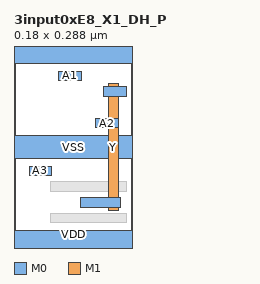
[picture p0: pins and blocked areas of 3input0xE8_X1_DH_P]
MACRO 3input0xE8_X1_DH_P
  CLASS CORE ;
  ORIGIN 0 0 ;
  FOREIGN 3input0xE8_X1_DH_P 0 0 ;
  SIZE 0.1800 BY 0.2880 ;
  SYMMETRY X Y ;
  SITE coresite ;
  PIN A1
    DIRECTION INPUT ;
    USE SIGNAL ;
    PORT
      LAYER M0 ;
        RECT 0.0680 0.2450 0.1020 0.2590 ;
    END
  END A1
  PIN A2
    DIRECTION INPUT ;
    USE SIGNAL ;
    PORT
      LAYER M0 ;
        RECT 0.1230 0.1730 0.1580 0.1870 ;
    END
  END A2
  PIN A3
    DIRECTION INPUT ;
    USE SIGNAL ;
    PORT
      LAYER M0 ;
        RECT 0.0230 0.1010 0.0570 0.1150 ;
    END
  END A3
  PIN Y
    DIRECTION OUTPUT ;
    USE SIGNAL ;
    PORT
      LAYER M1 ;
        RECT 0.1430 0.0480 0.1580 0.2400 ;
      LAYER M0 ;
        RECT 0.1010 0.0530 0.1620 0.0670 ;
        RECT 0.1350 0.2210 0.1700 0.2350 ;
    END
  END Y
  PIN VDD
    DIRECTION INOUT ;
    USE POWER ;
    SHAPE ABUTMENT ;
    PORT
      LAYER M0 ;
        RECT 0.0000 -0.0180 0.1800 0.0180 ;
        RECT 0.0000 0.2700 0.1800 0.3060 ;
    END
  END VDD
  PIN VSS
    DIRECTION INOUT ;
    USE GROUND ;
    SHAPE ABUTMENT ;
    PORT
      LAYER M0 ;
        RECT 0.0000 0.1260 0.1800 0.1620 ;
    END
  END VSS
  OBS
    LAYER V0 ;
      RECT 0.1430 0.0530 0.1570 0.0670 ;
      RECT 0.1430 0.2210 0.1570 0.2350 ;
    LAYER M0 ;
      RECT 0.0560 0.0290 0.1700 0.0430 ;
      RECT 0.0560 0.0770 0.1700 0.0910 ;
  END
END 3input0xE8_X1_DH_P
